One B-rep face of a CAD part: STEP entity #163.
In plain terms, the planar face has unit normal (1, 0, 0).
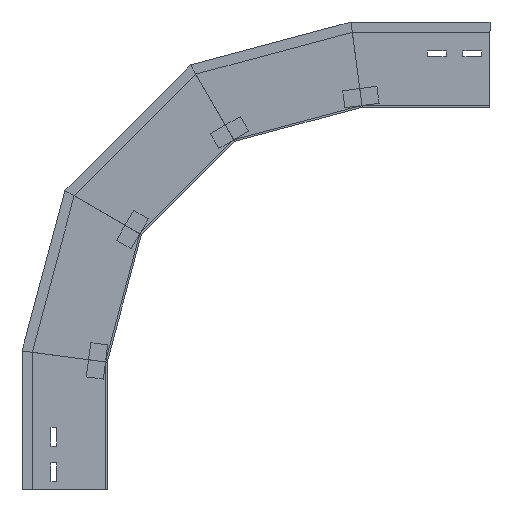
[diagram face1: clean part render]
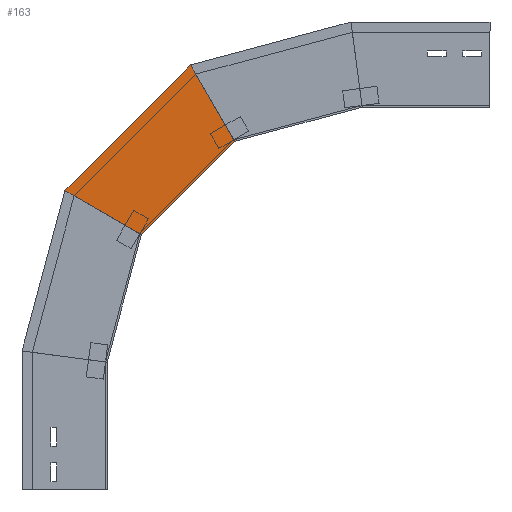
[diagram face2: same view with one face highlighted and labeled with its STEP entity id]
Its self-contained STEP definition (entity closure, numbers rounded to 3 decimals):
#15 = LINE ( 'NONE', #273, #1436 ) ;
#48 = CARTESIAN_POINT ( 'NONE',  ( 0., -19.205, 278.806 ) ) ;
#87 = VERTEX_POINT ( 'NONE', #216 ) ;
#92 = ORIENTED_EDGE ( 'NONE', *, *, #1036, .T. ) ;
#142 = DIRECTION ( 'NONE',  ( 0., -0.5, -0.866 ) ) ;
#163 = ADVANCED_FACE ( 'NONE', ( #774 ), #480, .T. ) ;
#165 = LINE ( 'NONE', #883, #1567 ) ;
#216 = CARTESIAN_POINT ( 'NONE',  ( 0., 49.541, 351.482 ) ) ;
#220 = CARTESIAN_POINT ( 'NONE',  ( 0., -40.117, 299.719 ) ) ;
#273 = CARTESIAN_POINT ( 'NONE',  ( 0., -173.604, 367.949 ) ) ;
#316 = EDGE_LOOP ( 'NONE', ( #92, #1119, #1445, #946 ) ) ;
#347 = CARTESIAN_POINT ( 'NONE',  ( 0., -78.128, 277.773 ) ) ;
#395 = VECTOR ( 'NONE', #623, 1000. ) ;
#401 = DIRECTION ( 'NONE',  ( 0., -0.707, 0.707 ) ) ;
#444 = DIRECTION ( 'NONE',  ( 1., 0., 0. ) ) ;
#480 = PLANE ( 'NONE',  #1252 ) ;
#520 = VECTOR ( 'NONE', #401, 1000. ) ;
#572 = CARTESIAN_POINT ( 'NONE',  ( 0., 51.506, 349.517 ) ) ;
#623 = DIRECTION ( 'NONE',  ( 0., -0.866, -0.5 ) ) ;
#652 = EDGE_CURVE ( 'NONE', #869, #1663, #15, .T. ) ;
#683 = CARTESIAN_POINT ( 'NONE',  ( 0., -97.955, 498.978 ) ) ;
#755 = EDGE_CURVE ( 'NONE', #87, #960, #1815, .T. ) ;
#774 = FACE_OUTER_BOUND ( 'NONE', #316, .T. ) ;
#869 = VERTEX_POINT ( 'NONE', #683 ) ;
#883 = CARTESIAN_POINT ( 'NONE',  ( 0., -19.205, 278.806 ) ) ;
#946 = ORIENTED_EDGE ( 'NONE', *, *, #755, .F. ) ;
#960 = VERTEX_POINT ( 'NONE', #220 ) ;
#1036 = EDGE_CURVE ( 'NONE', #87, #869, #1461, .T. ) ;
#1119 = ORIENTED_EDGE ( 'NONE', *, *, #652, .T. ) ;
#1252 = AXIS2_PLACEMENT_3D ( 'NONE', #48, #444, #1479 ) ;
#1436 = VECTOR ( 'NONE', #142, 1000. ) ;
#1445 = ORIENTED_EDGE ( 'NONE', *, *, #1888, .F. ) ;
#1461 = LINE ( 'NONE', #572, #520 ) ;
#1479 = DIRECTION ( 'NONE',  ( 0., 0., -1. ) ) ;
#1567 = VECTOR ( 'NONE', #1762, 1000. ) ;
#1663 = VERTEX_POINT ( 'NONE', #1685 ) ;
#1685 = CARTESIAN_POINT ( 'NONE',  ( 0., -149.719, 409.32 ) ) ;
#1762 = DIRECTION ( 'NONE',  ( 0., -0.707, 0.707 ) ) ;
#1815 = LINE ( 'NONE', #347, #395 ) ;
#1888 = EDGE_CURVE ( 'NONE', #960, #1663, #165, .T. ) ;
